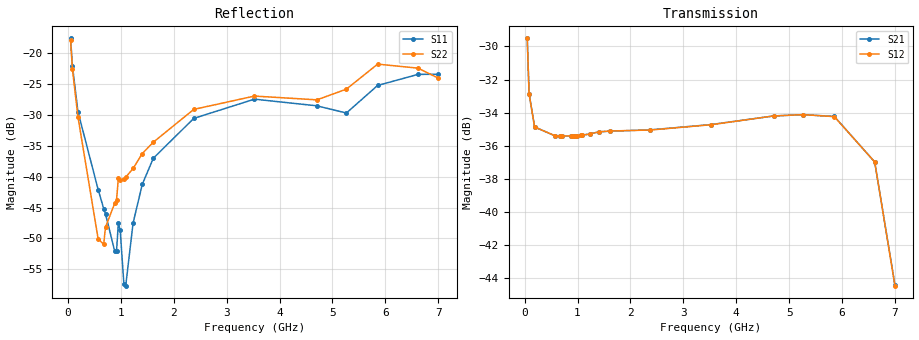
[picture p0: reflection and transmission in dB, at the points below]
! Integrated Device Technology
! Corporate Headquarters
! 6024 Silver Creek Valley Road
! San Jose, CA 95138  USA
! Phone:  1-408-284-8200
! Toll Free:  1-800-223-1366
! Webpage:  http://www.idt.com/
! Timing and RF Division
! 515 Groton Road, Suite 102
! Westford, MA 01886-6024
! Device:  F2258
! Description: Voltage Variable RF Attenuator
! Frequency:  50.0 -  6000.00 MHz
! Package:  3x3 mm Thin QFN Plastic Package: 16 pin
! Ports:  2 RF, 2 DC
!  Pin  1  = NC
!  Pin  2  = NC
!  Pin  3  = RF2  = Port 2
!  Pin  4  = GND
!  Pin  5  = Vdd
!  Pin  6  = NC
!  Pin  7  = VCTRL
!  Pin  8  = NC
!  Pin  9  = GND
!  Pin 10  = RF1  = Port 1
!  Pin 11  = NC
!  Pin 12  = NC
!  Pin 13  = NC
!  Pin 14  = NC
!  Pin 15  = NC
!  Pin 16  = NC
! Vcntrl:  2.250 Volts
! Vdd:  +3.300 Volts
! Current:  1.149 mA
! Data:  The device was measured on a the F2258 evaluation board which has
!  individual transmission lines to the RF pins.  Data was collected
!  using a calibrated network analyzer.  The evaluation board was
!  de-embedded using a TRL calibration technique.
!  The reference plane is the edge of the package pin.
! Misc:  SN 10
!  Action Tracker AT0285
! Date Measured:  2014-12-10
! Date:  2016-01-13  MJV
! Note:
!  Integrated Device Technology supplies this data as a sample of measured
!  data at the package pin for this product.  Your particular data for this
!  product may vary.
!  Data was taken at 25 degrees C.
!  Integrated Device Technology reserves the right to change this data at anytime.
!Freq_(GHz)  S11M_(dB)  S11P_(deg)  S21M_(dB)  S21P_(deg)  S12M_(dB)  S12P_(deg)  S22M_(dB)  S22P_(deg)
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# GHz S dB R 50
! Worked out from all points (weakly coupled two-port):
!   201 points, 50 MHz to 7 GHz, reference 50 ohm
!   highest |S21| = -29.51 dB at 50 MHz (marker M1); lowest = -44.4 dB at 7 GHz (marker M2)
!   lowest |S11| = -57.7 dB at 1.093 GHz (marker M3), VSWR 1.00, Z = 49.9 + j0.115 ohm
!   |S11| at or under -10 dB: start of sweep to end of sweep
!   |S22| runs from -51.5 to -17.9 dB; largest |S21 - S12| = 6.7e-05
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0.05  -17.55 -111.0  -29.51 -68.4  -29.51 -68.4  -17.88 -111.2
0.08475  -21.98 -107.4  -32.86 -48.7  -32.86 -48.6  -22.55 -107.1
0.189  -29.42 -109.5  -34.86 -24.7  -34.87 -24.7  -30.25 -108.6
0.57125  -42.08 -124.7  -35.40 -10.3  -35.39 -10.3  -50.09 -159.4
0.6755  -45.15 -132.0  -35.42 -9.4  -35.42 -9.4  -50.94 139.7
0.71025  -46.03 -137.6  -35.42 -9.3  -35.41 -9.2  -48.16 129.2
0.884  -52.05 166.2  -35.41 -8.4  -35.41 -8.4  -44.31 112.8
0.91875  -52.00 149.5  -35.40 -8.4  -35.41 -8.3  -43.76 110.8
0.9535  -47.45 -162.8  -35.41 -8.3  -35.42 -8.2  -40.24 119.1
0.98825  -48.69 -174.0  -35.40 -8.1  -35.40 -8.1  -40.57 116.7
1.05775  -57.43 156.3  -35.38 -8.0  -35.38 -8.0  -40.31 101.6
1.0925  -57.66 118.0  -35.36 -7.9  -35.36 -7.9  -40.07 97.5
1.2315  -47.50 47.3  -35.29 -7.9  -35.29 -7.9  -38.65 76.0
1.40525  -41.22 33.7  -35.16 -8.6  -35.16 -8.6  -36.23 63.6
1.61375  -36.99 32.8  -35.12 -9.6  -35.11 -9.6  -34.39 51.3
2.37825  -30.53 48.2  -35.04 -13.2  -35.05 -13.2  -29.07 42.3
3.525  -27.41 91.6  -34.72 -19.7  -34.73 -19.7  -26.91 66.7
4.7065  -28.49 95.6  -34.20 -28.8  -34.20 -28.8  -27.52 58.0
5.2625  -29.66 54.3  -34.12 -35.0  -34.12 -34.9  -25.79 20.7
5.85325  -25.19 29.9  -34.23 -45.6  -34.24 -45.5  -21.73 -2.9
6.61775  -23.39 49.7  -36.98 -68.7  -36.98 -68.7  -22.38 -44.6
7  -23.38 84.4  -44.42 -61.7  -44.46 -61.3  -24.00 -129.8
